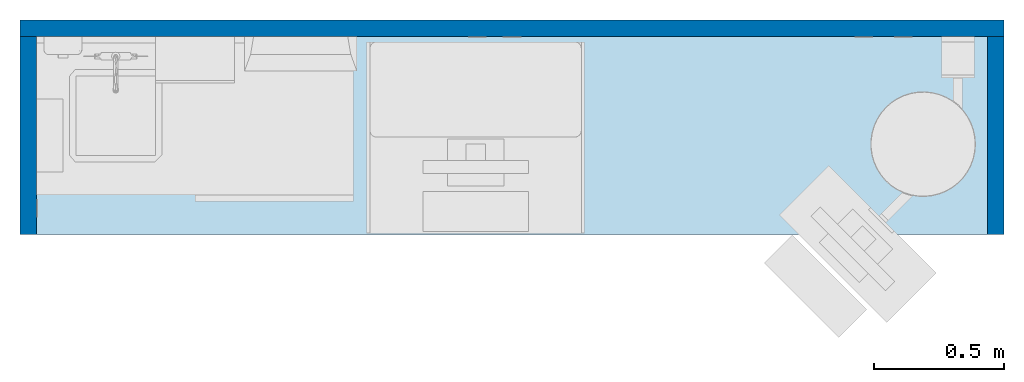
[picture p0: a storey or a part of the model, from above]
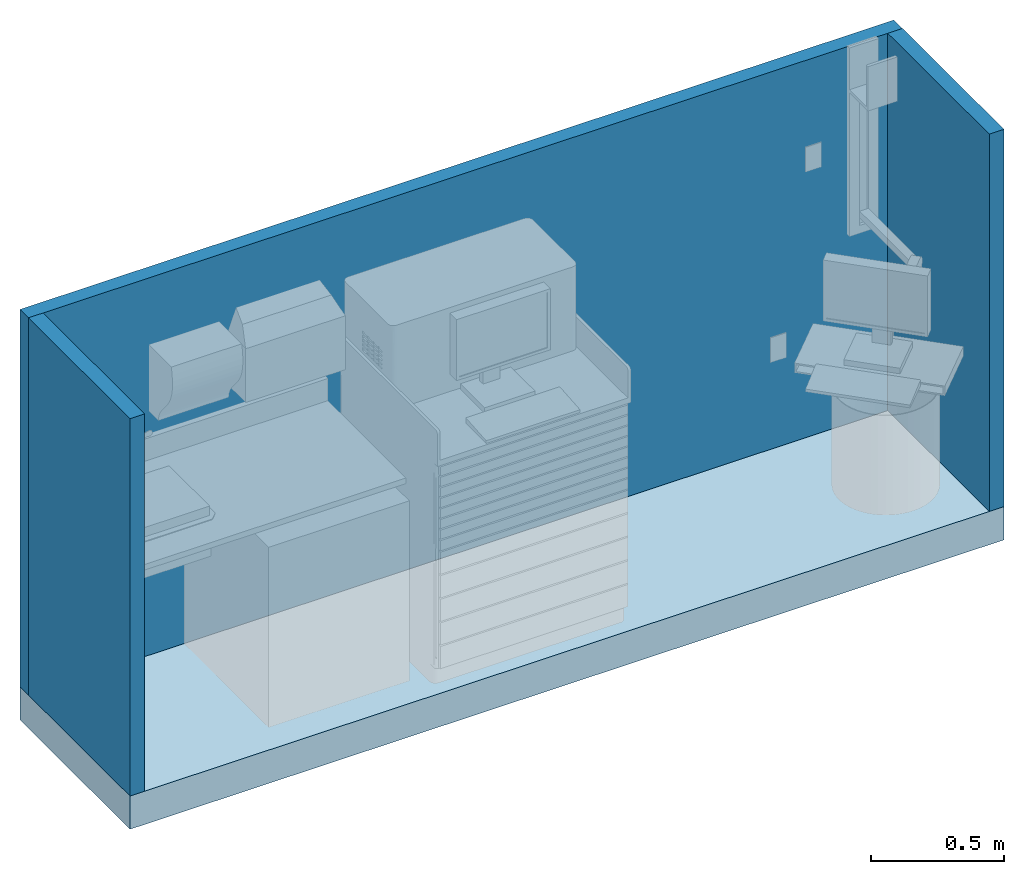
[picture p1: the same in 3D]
Properties of the parts of a building model (IFC2X3)

# File
Description: ViewDefinition [CoordinationView_V2.0]
File name: (ROOM CODE)
Time: 2018-06-28T00:42:49
Written by: The EXPRESS Data Manager Version 5.02.0100.07 : 28 Aug 2013
Made in: 20170223_1515(x64) - Exporter 18.0.0.420 - Alternate UI 18.0.0.420
Comment: STEP Physical File produced by: The EXPRESS Data Manager Version 5.02.0100.07 : 28 Aug 2013 * Module: EDMstepFileFactory/EDMstandAlone * Creation date: Thu Jun 28 00:42:49 2018 * Host: L106-OKC * Database: C:\Users\BHR~1.SPU\AppData\Local\Temp\{BC72B84E-1DEE-4059-8F86-124960F285E9}\ifc * Database version: 5507 * Database creation date: Thu Jun 28 00:42:48 2018 * Schema: IFC2X3 * Model: DataRepository.ifc * Model creation date: Thu Jun 28 00:42:48 2018 * Header model: DataRepository.ifc_HeaderModel * Header model creation date: Thu Jun 28 00:42:48 2018 * EDMuser: sdai-user * EDMgroup: sdai-group * License ID and type: 5605 : Permanent license. Expiry date: * EDMstepFileFactory options: 020000

# IfcProject, (ROOM CODE)
LongName: ROOM NAME (ROOM CODE); Phase: DRAFT

# IfcSite, Default
RefLatitude: 42, 21, 31, 181945; RefLongitude: -71, -3, -24, -263305; RefElevation: 0 ft

# IfcBuilding, OUTPATIENT / PACT CLINIC (Ch. 265)
LongName: OUTPATIENT / PACT CLINIC (Ch. 265)
Pset_BuildingCommon - NumberOfStoreys: 1

# IfcBuildingStorey, DATUM
In: OUTPATIENT / PACT CLINIC (Ch. 265)
LongName: DATUM; Elevation: 0 ft

# IfcSpace, RCA06
In: DATUM
LongName: ALCOVE, MEDICATION; InteriorOrExteriorSpace: INTERNAL
Pset_SpaceCommon - Reference: ALCOVE, MEDICATION RCA06; Category: Rooms

# IfcBuildingElementProxy: A5075 - Dispenser, Soap, A5075 - Dispenser, Soap:A5075 - Dispenser, Soap:796479
In: RCA06
Type - Classification: VV (Uniformat)
Pset_BuildingElementProxyCommon - Reference: A5075 - Dispenser, Soap

# IfcBuildingElementProxy: A5082 - Dispenser, Paper Towel, Sensor, Hands Free, A5082 - Dispenser, Paper Towel, Sensor, Hands Free:A5082 - Dispenser, Paper Towel, Sensor, Hands Free:796478
In: RCA06
Type - Classification: CC (Uniformat)
Pset_BuildingElementProxyCommon - Reference: A5082 - Dispenser, Paper Towel, Sensor, Hands Free

# IfcBuildingElementProxy: A5107 - Dispenser, Glove, Surgical-Examination, Wall Mntd 10"x 4", A5107 - Dispenser, Glove, Surgical-Examination, Wall Mntd:A5107 - Dispenser, Glove, Surgical-Examination, Wall Mntd 10"x 4":1856490
In: RCA06
Type - Classification: VV (Uniformat)
Pset_BuildingElementProxyCommon - Reference: A5107 - Dispenser, Glove, Surgical-Examination, Wall Mntd 10"x 4"

# IfcBuildingElementProxy: A5108 - Waste Disposal Unit, Sharps 17"x 13", A5108 - Waste Disposal Unit, Sharps:A5108 - Waste Disposal Unit, Sharps 17"x 13":1714158
In: DATUM
Type - Classification: VV (Uniformat)
Pset_BuildingElementProxyCommon - Reference: A5108 - Waste Disposal Unit, Sharps 17"x 13"

# IfcBuildingElementProxy: CS010 - Sink, SS, Single Compartment, 7.5x12x12 ID, CS010 - Sink, SS, Single Compartment, 7.5x12x12 ID:CS010 - Sink, SS, Single Compartment, 7.5x12x12 ID:796473
In: RCA06
Type - Classification: CC (Uniformat)
Pset_BuildingElementProxyCommon - Reference: CS010 - Sink, SS, Single Compartment, 7.5x12x12 ID

# IfcBuildingElementProxy: CT020 - Countertop, Solid Surface - No Opening (1), CT020 - Countertop, Solid Surface - No Opening (1):CT020 - Countertop, Solid Surface - No Opening (1):796472
In: RCA06
Type - Classification: CC (Uniformat)
Pset_BuildingElementProxyCommon - Reference: CT020 - Countertop, Solid Surface - No Opening (1)

# IfcBuildingElementProxy: Duplex (3)
In: RCA06
Pset_BuildingElementProxyCommon - Reference: Duplex
Name (Outlet, Duplex, Wall:Duplex:...)
1567801
1567854
1819461

# IfcBuildingElementProxy: F2000 - Basket, Wastepaper, F2000 - Basket, Wastepaper:F2000 - Basket, Wastepaper:796475
In: RCA06
Type - Classification: VV (Uniformat)
Pset_BuildingElementProxyCommon - Reference: F2000 - Basket, Wastepaper

# IfcBuildingElementProxy: M1801 - Computer with Flat Panel Monitor, M1801 - Computer with Flat Panel Monitor:M1801 - Computer with Flat Panel Monitor:1284998
In: DATUM
Type - Classification: VV (Uniformat)
Pset_BuildingElementProxyCommon - Reference: M1801 - Computer with Flat Panel Monitor

# IfcBuildingElementProxy: M1803 - Workstation, Computer, Wall Mounted, M1803 - Workstation, Computer, Wall Mounted:M1803 - Workstation, Computer, Wall Mounted:1284411
In: RCA06
Type - Classification: VV (Uniformat)
Pset_BuildingElementProxyCommon - Reference: M1803 - Workstation, Computer, Wall Mounted

# IfcBuildingElementProxy: M3150 - Distribution System, Medication, Automatic, M3150 - Distribution System, Medication, Automatic:M3150 - Distribution System, Medication, Automatic:1338582
In: RCA06
Type - Classification: VV (Uniformat)
Pset_BuildingElementProxyCommon - Reference: M3150 - Distribution System, Medication, Automatic

# IfcBuildingElementProxy: R6200 - Refrigerator, U-C or F-S, 5 Cu Ft (1), R6200 - Refrigerator, U-C or F-S, 5 Cu Ft (1):R6200 - Refrigerator, U-C or F-S, 5 Cu Ft (1):1143111
In: RCA06
Type - Classification: VV (Uniformat)
Pset_BuildingElementProxyCommon - Reference: R6200 - Refrigerator, U-C or F-S, 5 Cu Ft (1)

# IfcBuildingElementProxy: Telephone/Data (2)
In: RCA06
Pset_BuildingElementProxyCommon - Reference: Telephone/Data
Name (Outlet, Communications:Telephone/Data:...)
1567713
1567736

# IfcSlab: Floor:Generic - 6", Floor:Generic - 6":796450
In: DATUM
PredefinedType: FLOOR; Classification: B1010 Floor Construction (Uniformat); Material: <Unnamed> 0.5 ft
Pset_SlabCommon - LoadBearing: no; Reference: Generic - 6"; IsExternal: no; PitchAngle: 0 deg

# IfcWallStandardCase: Basic Wall:Systems Wall (3)
In: DATUM
Type - PredefinedType: STANDARD; Material: <Unnamed> 0.208333 ft
Classification: B2010 Exterior Walls (Uniformat)
Pset_WallCommon - Reference: Systems Wall; LoadBearing: no; ExtendToStructure: no; IsExternal: yes
Name (Basic Wall:Systems Wall:...)
796440
1496649
1496726
